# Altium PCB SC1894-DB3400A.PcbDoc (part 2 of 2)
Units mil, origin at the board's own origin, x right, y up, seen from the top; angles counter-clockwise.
Board outline 1800 x 1000 mil, 4 copper layers (L1 TOP, L2 GND, L3 PWR, L4  BOT), stack 35.4 mil thick; 130 components, 74 nets, 290 pads, 625 vias.

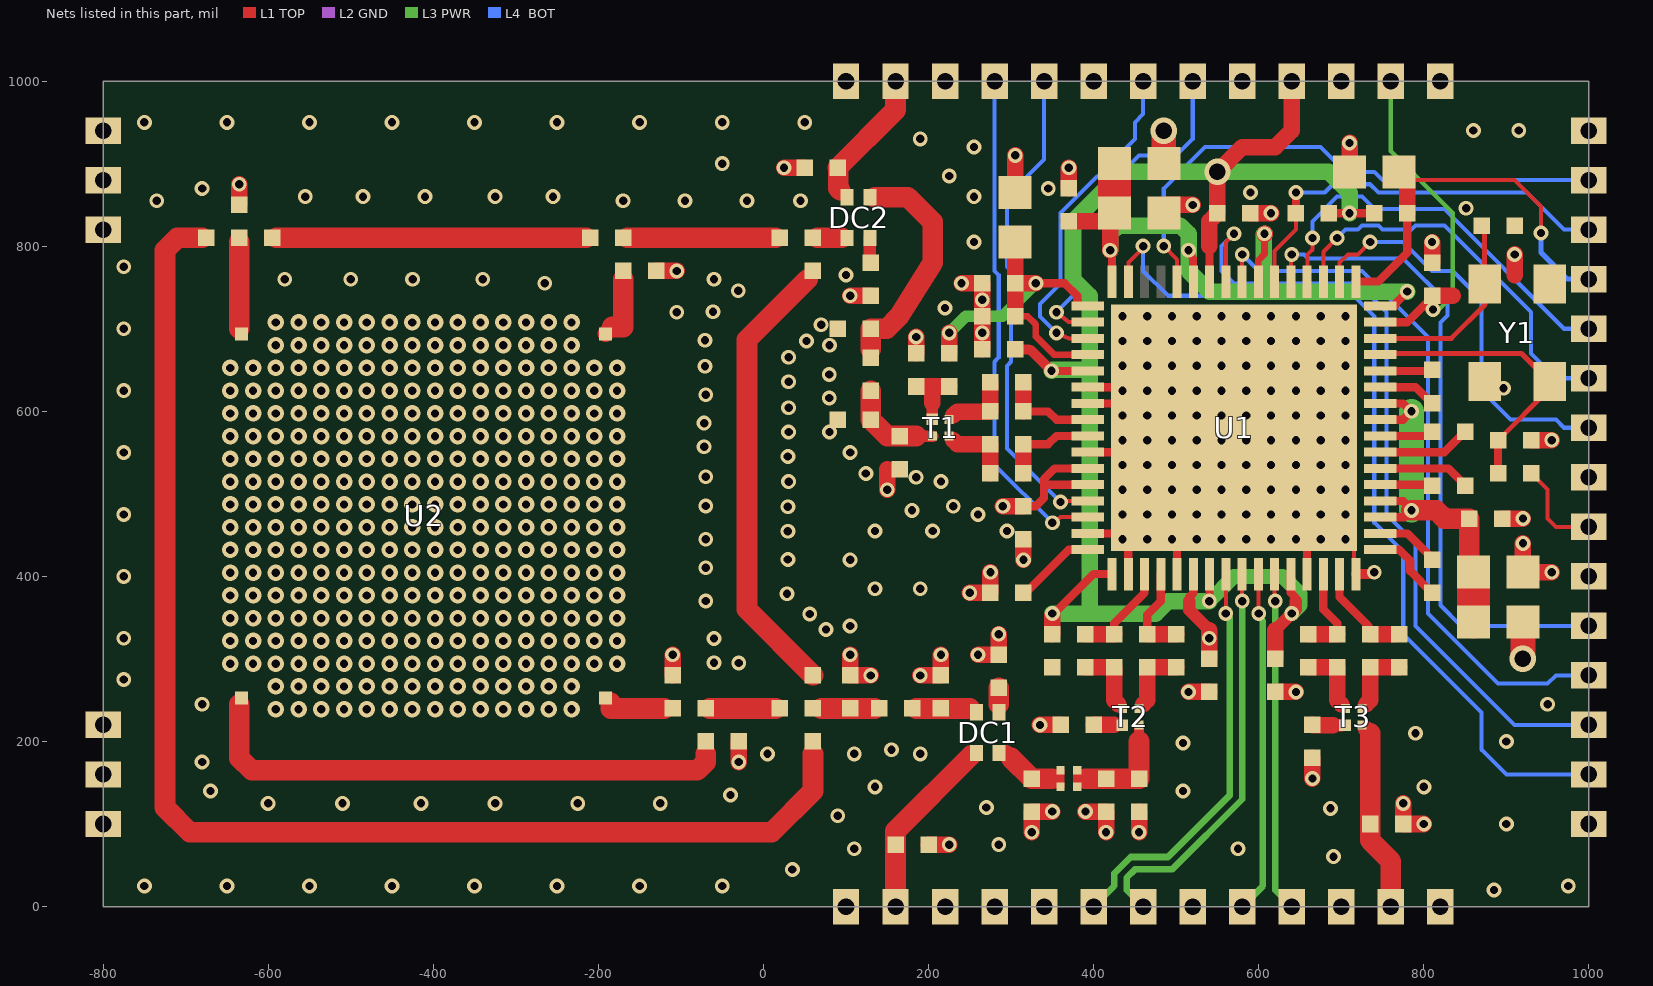
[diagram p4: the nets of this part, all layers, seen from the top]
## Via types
v1: diameter 20, hole 10, L1 TOP to L4  BOT, tented both sides, 308 vias
v2: diameter 18/18/18/18 (per signal layer), hole 10, L1 TOP to L4  BOT, tented both sides, 214 vias
v3: diameter 18/18/18/18 (per signal layer), hole 10, L1 TOP to L4  BOT, 100 vias
v4: diameter 32/32/32/32 (per signal layer), hole 20, L1 TOP to L4  BOT, tented both sides, 3 vias

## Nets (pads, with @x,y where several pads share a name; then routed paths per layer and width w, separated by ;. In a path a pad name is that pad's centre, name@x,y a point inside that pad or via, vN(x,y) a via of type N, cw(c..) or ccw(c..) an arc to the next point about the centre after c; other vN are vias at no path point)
+1.8V: C6.1 C8.1 C9.1 C12.1 C31.1 C34.1 FT1.2 FT2.1 FT3.1 P30.1 U1.1 U1.4 U1.11 U1.12 U1.22 U1.47 | length 1279.9
  L1 TOP w5: C8.1@810,740 C8.1@812.05,740
  L1 TOP w8: C12.1@305,715 320,715 330,705 330,690.58 352,668.58 U1.4@392.83,668.58
  L1 TOP w10: C31.1@315,485 330,485 340,495 340,511.1 ; v2(330,755) 365,755 380,740 380,727.64 U1.1@392.83,727.64 ; U1.12@392.83,511.1 340,511.1 ; U1.11@392.83,530.79 352.8,530.79 340,517.99 340,511.1 ; 515.79,370 515.79,375 520.79,380 U1.22@520.79,402.83 ; U1.47@747.17,707.95 780,707.95 C8.1@812.05,740
  L1 TOP w15: 515.79,370 515.79,359.21 540,335
  L1 TOP w20: FT3.1@225,670 v2(225,695) ; v2(290,485) C31.1@315,485 ; C12.1@305,715 C9.1@305,755 ; C6.1@305,805 C9.1@305,755 ; v2(330,755) C9.1@305,755 ; C34.1@540,300 v2(540,325) 540,335 ; C8.1@812.05,740 835,740
  L1 TOP w30: FT1.2@485,900 v4(485,940) ; v4(920,300) FT2.1@920,345
  L3 PWR w5: P30.1@760,1000 760,915 835,840 835,740 818.43,723.43 v2(811.02,723.43)
  L3 PWR w14: v2(225,695) 245,715 290,715 v2(330,755)
+3.3V: C3.2 C14.1 C33.1 C35.1 P32.1 R1.2 R2.1 U1.5 U1.17 U1.23 U1.28 U1.58 | length 2007.7
  L1 TOP w10: v2(349,649) 349.1,648.9 U1.5@392.83,648.9 ; v2@350,352.49 v2(350,355) 352.17,355 400,402.83 U1.17@422.36,402.83 ; v2(540,370) 540.47,370.47 U1.23@540.47,402.83 ; 540,800 540.47,799.53 U1.58@540.47,757.17 ; U1.28@638.9,402.83 638.9,380 645,373.9 645,370 ; R1.2@685,840 v2(710,840) R2.1@740,840
  L1 TOP w12: C14.1@305,675 321.34,675 322.17,674.17 323.83,674.17 v2(349,649)
  L1 TOP w15: 620,335 v2(640,355) 645,360 645,370
  L1 TOP w20: C33.1@350,330 v2@350,352.49 ; 540,800 540,830 C3.2@550,840 v4(550,890) 580,920 620,920 640,940 P32.1@640,1000 ; C35.1@620,300 620,335
  L3 PWR w18: v2(540,370) 570,400 628.75,400 650,378.75 650,365 v2(640,355)
  L3 PWR w20: v2(349,649) 350,650 395,650 ; v2(350,355) 395,355 ; v2(540,370) 490,370 475,355 395,355 ; v2(710,840) 710,865 685,890 v4(550,890) 435,890 375,830 375,760 395,740 395,650 ; 395,355 395,650
ADCIN0N: P7.1 U1.25 | length 495.6
  L1 TOP w5: U1.25@579.84,402.83 579.84,370 v2(580,370)
  L3 PWR w8: P7.1@460,0 440,20 440,35 450,45 495,45 580,130 v2(580,370)
ADCIN0P: P6.1 U1.24 | length 499.8
  L1 TOP w5: v2(560,355) 560.16,355 U1.24@560.16,402.83
  L3 PWR w8: P6.1@400,0 425,25 425,40 445,60 490,60 565,135 565,350 v2(560,355)
ADCIN1N: P10.1 U1.27 | length 411.9
  L1 TOP w5: U1.27@619.21,402.83 619.21,370 v2(620,370)
  L3 PWR w8: v2(620,370) 620,20 P10.1@640,0
ADCIN1P: P9.1 U1.26 | length 414.8
  L1 TOP w5: U1.26@599.53,402.83 599.53,355 v2(600,355)
  L3 PWR w8: P9.1@580,0 605,25 605,345 v2(600,355)
DGPIN0: P15.1 U1.63 | length 1104.3
  L1 TOP w5: U1.63@442.05,757.17 442.05,780 460,797.95 v2(460,800)
  L4  BOT w5: v2(460,800) 460,770 490,740 715,740 740,715 740,465 775,430 775,330 870,235 870,190 900,160 P15.1@1000,160
DGPIN1: P17.1 U1.56 | length 868.8
  L1 TOP w5: U1.56@579.84,757.17 579.84,790 v2(580,790)
  L4  BOT w5: v2(580,790) 600,770 725,770 805,690 805,355 890,270 950,270 960,280 P17.1@1000,280
EXTCLKIN: C15.2 P20.1 | length 117.4
  L1 TOP w5: C15.2@930,525 950,505 950,470 960,460 P20.1@1000,460
GND: C1.2 C2.1 C3.1 C4.2 C6.2 C8.2 C9.2 C10.2 C11.2 C12.2 C14.2 C22.2 C26.1 C28.1 C29.2 C30.2 C31.2 C33.2 C34.2 C35.2 C36.2 C45.2 C46.2 C47.2 C48.2 P1.1 P3.1 P4.1 P5.1 P8.1 P11.1 P13.1 P14.1 P19.1 P21.1 P28.1 P29.1 P31.1 P33.1 P36.1 P39.1 P41.1 P42.1 P43.1 P44.1 P45.1 P46.1 P47.1 R10.2 R12.1 R13.1 R15.2 R16.2 R21.1 R23.2 R43.1 R45.1 R98.1 R99.1 R104.1 R105.1 U1.6 U1.7 U1.10 U1.15 U1.18 U1.21 U1.29 U1.32 U1.65 Y1.2 Y1.4 | length 2638.1
  L1 TOP w5: v3(705,445) 715.47,445 715.47,405 U1.32@717.64,402.83
  L1 TOP w10: U1.15@392.83,452.05 U1.65@442.05,452.05 ; U1.10@392.83,550.47 U1.65@442.05,550.47 ; U1.7@392.83,609.53 U1.65@570,609.53 ; U1.6@392.83,629.21 570,629.21 U1.65@570,609.53 ; U1.18@442.05,402.83 U1.65@442.05,452.05 ; U1.21@501.1,402.83 U1.65@501.1,452.05 ; U1.29@658.58,402.83 658.58,580 U1.65@570,580 ; U1.65@442.05,452.05 U1.65@442.05,550.47 ; U1.65@442.05,452.05 U1.65@501.1,452.05 ; U1.65@442.05,550.47 U1.65@501.1,550.47 ; U1.65@501.1,452.05 U1.65@501.1,550.47 ; U1.65@501.1,550.47 501.1,580 U1.65@570,580 ; U1.65@501.1,550.47 570,550.47 U1.65@570,580 ; U1.65@570,580 U1.65@570,609.53
  L1 TOP w12: U1.32@717.64,402.83 737.83,402.83 v2(740,405)
  L1 TOP w20: R98.1@-635,850 v2(-635,875) ; R105.1@-130,770 v2(-105,770) ; R104.1@-110,280 v2(-110,305) ; v2(-30,175) R99.1@-30,200 ; v2(25,895) C48.2@50,895 ; v2(105,305) R13.1@105,280 v2(130,280) ; v2(105,740) R10.2@130,740 ; v2(150,505) 150,530 ; C26.1@185,670 v2(185,690) ; v2(190,280) R15.2@215,280 v2(215,305) ; C47.2@200,75 v2(225,75) ; v2(240,755) C9.2@265,755 v2(265,735) C12.2@265,715 v2(265,695) C14.2@265,675 ; v2(250,380) R12.1@275,380 v2(275,405) ; v2(260,305) R16.2@285,305 v2(285,330) ; C6.2@305,865 v2(305,910) ; v2(315,420) C31.2@315,445 ; v2(325,90) R21.1@325,115 v2(350,115) ; v2(335,220) C28.1@360,220 ; C4.2@370,870 v2(370,895) ; v2(390,115) R23.2@415,115 v2(415,90) ; v2(455,90) C46.2@455,115 ; C2.1@485,840 485,850 v2(520,850) ; v2(515,260) C34.2@540,260 ; C3.1@590,840 v2(615,840) ; C35.2@620,260 v2(645,260) ; v2(665,155) C36.2@665,180 ; C1.2@710,890 v2(710,925) ; v2(775,125) C45.2@775,100 v2(800,100) ; C8.2@810,780 v2(810,805) ; C29.2@895,470 v2(920,470) ; 910,765 v2(910,790) ; v2(920,440) C30.2@920,405 v2(955,405) ; C11.2@930,565 v2(955,565)
  L2 GND w20: P1.1@100,0 100,1.81 P1.1@100.69,2.5 ; P3.1@219.7,2.5 220,2.2 P3.1@220,0 ; P31.1@700,999.24 P31.1@701.74,997.5 ; P13.1@820,2.33 P13.1@820.17,2.5
  L3 PWR w20: P1.1@100,0 100,1.94 P1.1@100.56,2.5 ; P3.1@220,0 P3.1@220,2.5
  other v1: -590.79,239.09 -563.23,239.09 -535.67,239.09 -508.11,239.09 -480.55,239.09 -452.99,239.09 -425.43,239.09 -397.87,239.09 -370.32,239.09 -342.76,239.09 -315.2,239.09 -287.64,239.09 -260.08,239.09 -232.52,239.09 -590.79,266.65 -563.23,266.65 -535.67,266.65 -508.11,266.65 -480.55,266.65 -452.99,266.65 -425.43,266.65 -397.87,266.65 -370.32,266.65 -342.76,266.65 -315.2,266.65 -287.64,266.65 -260.08,266.65 -232.52,266.65 -645.91,294.21 -618.35,294.21 -590.79,294.21 -563.23,294.21 -535.67,294.21 -508.11,294.21 -480.55,294.21 -452.99,294.21 -425.43,294.21 -397.87,294.21 -370.32,294.21 -342.76,294.21 -315.2,294.21 -287.64,294.21 -260.08,294.21 -232.52,294.21 -204.96,294.21 -177.4,294.21 -645.91,321.77 -618.35,321.77 -590.79,321.77 -563.23,321.77 -535.67,321.77 -508.11,321.77 -480.55,321.77 -452.99,321.77 -425.43,321.77 -397.87,321.77 -370.32,321.77 -342.76,321.77 -315.2,321.77 -287.64,321.77 -260.08,321.77 -232.52,321.77 -204.96,321.77 -177.4,321.77 -645.91,349.33 -618.35,349.33 -590.79,349.33 -563.23,349.33 -535.67,349.33 -508.11,349.33 -480.55,349.33 -452.99,349.33 -425.43,349.33 -397.87,349.33 -370.32,349.33 -342.76,349.33 -315.2,349.33 -287.64,349.33 -260.08,349.33 -232.52,349.33 -204.96,349.33 -177.4,349.33 -645.91,376.89 -618.35,376.89 -590.79,376.89 -563.23,376.89 -535.67,376.89 -508.11,376.89 -480.55,376.89 -452.99,376.89 -425.43,376.89 -397.87,376.89 -370.32,376.89 -342.76,376.89 -315.2,376.89 -287.64,376.89 -260.08,376.89 -232.52,376.89 -204.96,376.89 -177.4,376.89 -645.91,404.45 -618.35,404.45 -590.79,404.45 -563.23,404.45 -535.67,404.45 -508.11,404.45 -480.55,404.45 -452.99,404.45 -425.43,404.45 -397.87,404.45 -370.32,404.45 -342.76,404.45 -315.2,404.45 -287.64,404.45 -260.08,404.45 -232.52,404.45 -204.96,404.45 -177.4,404.45 -645.91,432.01 -618.35,432.01 -590.79,432.01 -563.23,432.01 -535.67,432.01 -508.11,432.01 -480.55,432.01 -452.99,432.01 -425.43,432.01 -397.87,432.01 -370.32,432.01 -342.76,432.01 -315.2,432.01 -287.64,432.01 -260.08,432.01 -232.52,432.01 -204.96,432.01 -177.4,432.01 -645.91,459.57 -618.35,459.57 -590.79,459.57 -563.23,459.57 -535.67,459.57 -508.11,459.57 -480.55,459.57 -452.99,459.57 -425.43,459.57 -397.87,459.57 -370.32,459.57 -342.76,459.57 -315.2,459.57 -287.64,459.57 -260.08,459.57 -232.52,459.57 -204.96,459.57 -177.4,459.57 -645.91,487.13 -618.35,487.13 -590.79,487.13 -563.23,487.13 -535.67,487.13 -508.11,487.13 -480.55,487.13 -452.99,487.13 -425.43,487.13 -397.87,487.13 -370.32,487.13 -342.76,487.13 -315.2,487.13 -287.64,487.13 -260.08,487.13 -232.52,487.13 -204.96,487.13 -177.4,487.13 -645.91,514.68 -618.35,514.68 -590.79,514.68 -563.23,514.68 -535.67,514.68 -508.11,514.68 -480.55,514.68 -452.99,514.68 -425.43,514.68 -397.87,514.68 -370.32,514.68 -342.76,514.68 -315.2,514.68 -287.64,514.68 -260.08,514.68 -232.52,514.68 -204.96,514.68 -177.4,514.68 -645.91,542.24 -618.35,542.24 -590.79,542.24 -563.23,542.24 -535.67,542.24 -508.11,542.24 -480.55,542.24 -452.99,542.24 -425.43,542.24 -397.87,542.24 -370.32,542.24 -342.76,542.24 -315.2,542.24 -287.64,542.24 -260.08,542.24 -232.52,542.24 -204.96,542.24 -177.4,542.24 -645.91,569.8 -618.35,569.8 -590.79,569.8 -563.23,569.8 -535.67,569.8 -508.11,569.8 -480.55,569.8 -452.99,569.8 -425.43,569.8 -397.87,569.8 -370.32,569.8 -342.76,569.8 -315.2,569.8 -287.64,569.8 -260.08,569.8 -232.52,569.8 -204.96,569.8 -177.4,569.8 -645.91,597.36 -618.35,597.36 -590.79,597.36 -563.23,597.36 -535.67,597.36 -508.11,597.36 -480.55,597.36 -452.99,597.36 -425.43,597.36 -397.87,597.36 -370.32,597.36 -342.76,597.36 -315.2,597.36 -287.64,597.36 -260.08,597.36 -232.52,597.36 -204.96,597.36 -177.4,597.36 -645.91,624.92 -618.35,624.92 -590.79,624.92 -563.23,624.92 -535.67,624.92 -508.11,624.92 -480.55,624.92 -452.99,624.92 -425.43,624.92 -397.87,624.92 -370.32,624.92 -342.76,624.92 -315.2,624.92 -287.64,624.92 -260.08,624.92 -232.52,624.92 -204.96,624.92 -177.4,624.92 -645.91,652.48 -618.35,652.48 -590.79,652.48 -563.23,652.48 -535.67,652.48 -508.11,652.48 -480.55,652.48 -452.99,652.48 -425.43,652.48 -397.87,652.48 -370.32,652.48 -342.76,652.48 -315.2,652.48 -287.64,652.48 -260.08,652.48 -232.52,652.48 -204.96,652.48 -177.4,652.48 -590.79,680.04 -563.23,680.04 -535.67,680.04 -508.11,680.04 -480.55,680.04 -452.99,680.04 -425.43,680.04 -397.87,680.04 -370.32,680.04 -342.76,680.04 -315.2,680.04 -287.64,680.04 -260.08,680.04 -232.52,680.04 -590.79,707.6 -563.23,707.6 -535.67,707.6 -508.11,707.6 -480.55,707.6 -452.99,707.6 -425.43,707.6 -397.87,707.6 -370.32,707.6 -342.76,707.6 -315.2,707.6 -287.64,707.6 -260.08,707.6 -232.52,707.6
  other v2: 885,20 -750,25 -650,25 -550,25 -450,25 -350,25 -250,25 -150,25 -50,25 975,25 35,45 690.51,60.47 110,70 575,70 285,75 900,100 90,110 687.05,118.94 270,120 -600,125 -510,125 -415,125 -325,125 -225,125 -125,125 -40,135 -670,140 508.27,140 135,145 800,145 -680,175 5,185 110,185 190,185 155,190 508.27,198.03 900,200 790,210 -680,245 950,245 -775,275 -60.04,295.28 -30,295 -775,325 -60.04,324.8 75.79,335.63 105,340 56.1,354.33 -69.88,370.08 28.54,378.94 135,385 190,385 -775,400 -69.88,410.43 29.53,420.28 105,420 -69.88,444.88 29.53,454.72 135,455 205,455 295,455 -775,475 260,475 180,480 29.53,484.25 -69.88,485.24 230,485 30.51,514.76 215,515 185,520 -69.88,520.67 124.02,524.61 29.53,545.28 -775,550 105,550 -71.85,557.09 30.51,574.8 80,575 -71.85,585.63 30.51,604.33 79.72,616.14 -69.88,620.08 -775,625 896.65,627.95 30.51,635.83 79.72,644.68 -70.87,654.53 30.51,665.35 80,680 52.17,685.04 -70.87,686.02 -775,700 69.88,704.72 -105,720 -61.02,720.47 220,725 -30.51,746.06 -265,755 -580,760 -500,760 -425,760 -340,760 -60.04,759.84 100,765 -775,775 255,805 851.3,845.91 -735,855 -170,855 -95,855 -20,855 45,855 -555,860 -485,860 -410,860 -325,860 -255,860 255,860 590,865 -680,870 345,870 225,885 -50,900 255,920 190,930 860,940 915,940 -750,950 -650,950 -550,950 -450,950 -350,950 -250,950 -150,950 -50,950 50,950
  other v3: 435,445 465,445 495,445 525,445 555,445 585,445 615,445 645,445 675,445 435,475 465,475 495,475 525,475 555,475 585,475 615,475 645,475 675,475 705,475 435,505 465,505 495,505 525,505 555,505 585,505 615,505 645,505 675,505 705,505 435,535 465,535 495,535 525,535 555,535 585,535 615,535 645,535 675,535 705,535 435,565 465,565 495,565 525,565 555,565 585,565 615,565 645,565 675,565 705,565 435,595 465,595 495,595 525,595 555,595 585,595 615,595 645,595 675,595 705,595 435,625 465,625 495,625 525,625 555,625 585,625 615,625 645,625 675,625 705,625 435,655 465,655 495,655 525,655 555,655 585,655 615,655 645,655 675,655 705,655 435,685 465,685 495,685 525,685 555,685 585,685 615,685 645,685 675,685 705,685 435,715 465,715 495,715 525,715 555,715 585,715 615,715 645,715 675,715 705,715
LOADENB: P27.1 U1.60 | length 671.8
  L1 TOP w5: v2(485,800) 500.36,784.64 500.36,784.25 501.1,783.51 U1.60@501.1,757.17
  L4  BOT w5: v2(485,800) 485,870 535,920 675,920 705,890 740,890 750,880 P27.1@1000,880
MGPO0: P34.1 U1.2 | length 416.8
  L1 TOP w5: v2(355,720) 370,707.95 U1.2@392.83,707.95
  L4  BOT w5: v2(355,720) 380,745 380,835 455,910 500,910 520,930 P34.1@520,1000
MGPO1: P35.1 U1.3 | length 404.3
  L1 TOP w5: v2(355,695) 370,688.27 U1.3@392.83,688.27
  L4  BOT w5: v2(355,695) 335,715 335,730 360,755 360,840 450,930 450,950 460,960 P35.1@460,1000
MGPO2: P37.1 U1.13 | length 594
  L1 TOP w5: v2(360,490) 360,491.42 U1.13@392.83,491.42
  L4  BOT w5: P37.1@340,1000 340,905 295,860 295,775 300,770 300,660 295,655 295,555 v2(360,490)
MGPO3: P38.1 U1.14 | length 613
  L1 TOP w5: v2(350,465) 360,471.73 U1.14@392.83,471.73
  L4  BOT w5: P38.1@280,1000 280,770 285,765 285,665 280,660 280,535 v2(350,465)
N16778023: C11.1 C15.1 U1.45 Y1.3 | length 357.4
  L1 TOP w6: U1.45@747.17,668.58 747.17,670 918.27,670 Y1.3@952.32,635.94 952.32,627.32 C11.1@890,565
  L1 TOP w10: C15.1@890,525 C11.1@890,565
N16778042: C29.1 C30.1 FT2.2 U1.35 U1.36 U1.41 U1.42 | length 499.8
  L1 TOP w10: U1.35@747.17,471.73 776.73,471.73 v2(785,480) 785,481.42 775,491.42 U1.36@747.17,491.42 ; U1.41@747.17,589.84 775,589.84 775,590 v2(785,600) 784.53,600 775,609.53 U1.42@747.17,609.53
  L1 TOP w25: v2(785,480) 815,480 825,470 C29.1@855,470 855,400 C30.1@860,405
  L1 TOP w40: FT2.2@860,345 C30.1@860,405
  L3 PWR w30: v2(785,480) v2(785,600)
N16778055: C51.2 L2.2 U1.8 | length 117
  L1 TOP w10: C51.2@315,600 315.16,599.84 345,599.84 355,589.84 U1.8@392.83,589.84
  L1 TOP w20: C51.2@315,600 L2.2@315,635
N16778107: C52.2 L6.1 U1.20 | length 114.6
  L1 TOP w10: C52.2@465,330 465,353.58 481.42,370 U1.20@481.42,402.83
  L1 TOP w20: C52.2@465,330 L6.1@500,330
N16778109: C2.2 C4.1 FT1.1 U1.48 U1.55 U1.59 U1.64 | length 924.4
  L1 TOP w8: U1.55@599.53,757.17 599.53,783 607,790.47 v2@607,814.24
  L1 TOP w10: v2@420,802.36 420.98,795.13 421,795 422.36,785 U1.64@422.36,757.17 ; v2(515,795) 520.46,785.01 520.46,760.33 520.79,760 U1.59@520.79,757.17 ; U1.48@747.17,727.64 765,727.64 765,730 v2(780,745)
  L1 TOP w20: C4.1@370,830 C2.2@420,830 ; v2(420,795) 420,802.36 C2.2@420,830 ; C2.2@425,840 420,835 C2.2@420,830 ; FT1.1@425,895 FT1.1@425,900 ; v2@607,814.24 v2(607,815)
  L1 TOP w40: C2.2@425,840 FT1.1@425,895
  L3 PWR w20: v2(420,795) 420,815 430,825 505,825 515,815 v2(515,795) 515,769.99 539.99,744.99 ; v2(607,815) 606.29,814.29 606.29,744.99 ; v2(780,745) 775,745 606.29,744.99 ; 540,744.99 606.29,744.99 ; 539.99,744.99 606.29,744.99
N16778151: R11.2 R13.2 R14.2 R17.1 R101.1 | length 80
  L1 TOP w5: R101.1@60,240 70,240 ; R14.2@135,240 R14.2@140,240
  L1 TOP w25: 70,240 R13.2@105,240 R14.2@135,240
N16778208: C10.1 U1.46 Y1.1 | length 241.2
  L1 TOP w6: U1.46@747.17,688.27 833.27,688.27 874.02,729.02 874.02,753.62 Y1.1@873.58,754.06 873.58,821.26 C10.1@870,824.84
N16778603: C26.2 FT3.2 T1.1 | length 98.5
  L1 TOP w14: T1.1@204.5,590.5 204.5,610
  L1 TOP w20: 204.5,610 204.5,629.5 C26.2@185,630 FT3.2@225,630
N16778643: DC1.3 R21.2 R22.2 R24.2 | length 98.3
  L1 TOP w10: 350,155 360,155 ; R24.2@360,145 360,155 ; R22.2@360,165 360,155
  L1 TOP w20: 294.41,185.59 300,180
  L1 TOP w25: 300,180 R21.2@325,155 350,155
N16778760: R12.2 U1.16 | length 99.5
  L1 TOP w10: R12.2@315,380 317.64,380 370,432.36 U1.16@392.83,432.36
N16778848: L7.2 R25.1 U1.31 | length 123.2
  L1 TOP w10: U1.31@697.95,402.83 697.95,375 732.95,340 732.95,332.05 L7.2@735,330 ; R25.1@765,330 R25.1@770,330
  L1 TOP w20: L7.2@735,330 R25.1@765,330
N16778850: DC1.2 R14.1 R15.1 | length 70
  L1 TOP w5: R14.1@180,240 R14.1@185,240
  L1 TOP w25: R14.1@185,240 R15.1@215,240 DC1.2@250,240
N16778878: L7.1 R26.2 U1.30 | length 114.8
  L1 TOP w10: U1.30@678.27,402.83 678.27,360 695,343.27 L7.1@695,330
  L1 TOP w20: R26.2@660,330 L7.1@695,330
N16778942: C46.1 R22.1 R23.1 R24.1 T2.2 | length 200
  L1 TOP w10: R24.1@380,145 380,155 ; R22.1@380,165 380,155 ; 390,155 380,155
  L1 TOP w12: 455,200 T2.2@455,220
  L1 TOP w25: 390,155 C46.1@455,155 ; R23.1@415,155 C46.1@455,155 ; 455,200 C46.1@455,155
N16779024: C51.1 L3.1 U1.9 | length 117
  L1 TOP w10: C51.1@315,560 315.16,560.16 345,560.16 355,570.16 U1.9@392.83,570.16
  L1 TOP w20: L3.1@315,525 C51.1@315,560
N16779035: C52.1 L5.2 U1.19 | length 123
  L1 TOP w10: C52.1@425,330 425,343.27 461.73,380 U1.19@461.73,402.83
  L1 TOP w20: L5.2@390,330 C52.1@425,330
N16779391: C18.1 L5.1 T2.4 | length 89.1
  L1 TOP w5: T2.4@430,245 T2.4@435,240
  L1 TOP w20: L5.1@390,290 C18.1@425,290 425,250 T2.4@430,245
N16779395: C18.2 L6.2 T2.3 | length 89.1
  L1 TOP w5: T2.3@455,240 T2.3@460,245
  L1 TOP w20: T2.3@460,245 465,250 C18.2@465,290 L6.2@500,290
N16779627: C13.1 U1.44 | length 63.3
  L1 TOP w10: U1.44@747.17,648.9 808.9,648.9 C13.1@810,650
N16779631: C13.2 U1.43 | length 70.8
  L1 TOP w10: U1.43@747.17,629.21 790,629.21 809.21,610 C13.2@810,610
N16779697: C25.1 U1.40 | length 64.8
  L1 TOP w10: U1.40@747.17,570.16 805.16,570.16 C25.1@810,575
N16779756: C25.2 U1.39 | length 113
  L1 TOP w10: U1.39@747.17,550.47 825,550.47 849.53,575 C25.2@850,575
N16779783: C27.1 U1.38 | length 111.9
  L1 TOP w10: U1.38@747.17,530.79 830,530.79 850,510.79 C27.1@850,510
N16779788: DC2.3 R10.1 | length 31.8
  L1 TOP w15: DC2.3@128.78,810.59 128.78,780 R10.1@130,780
N16779793: C27.2 U1.37 | length 63.9
  L1 TOP w10: U1.37@747.17,511.1 810,511.1 C27.2@810,510
N16779834: C32.1 U1.34 | length 77.3
  L1 TOP w10: U1.34@747.17,452.05 780,452.05 810,422.05 C32.1@810,420
N16779938: C32.2 U1.33 | length 91.8
  L1 TOP w10: U1.33@747.17,432.36 770,432.36 783.68,418.68 783.68,406.32 C32.2@810,380
N16779945: DC1.4 R16.1 | length 21.7
  L1 TOP w5: DC1.4@283.78,243.78 DC1.4@285,245
  L1 TOP w25: DC1.4@285,245 R16.1@285,265
N16780104: C20.1 R26.1 T3.4 | length 89.1
  L1 TOP w5: T3.4@700,245 T3.4@705,240
  L1 TOP w20: R26.1@660,290 C20.1@695,290 695,250 T3.4@700,245
N16780111: C20.2 R25.2 T3.3 | length 89.1
  L1 TOP w5: T3.3@725,240 T3.3@730,245
  L1 TOP w20: T3.3@730,245 735,250 C20.2@735,290 R25.2@770,290
N16780222: C17.1 L2.1 T1.4 | length 89.1
  L1 TOP w5: T1.4@225,590 T1.4@230,595
  L1 TOP w20: T1.4@230,595 234.68,599.68 274.68,599.68 C17.1@275,600 L2.1@275,635
N16780244: C17.2 L3.2 T1.3 | length 89.1
  L1 TOP w5: T1.3@225,570 T1.3@230,565
  L1 TOP w20: T1.3@230,565 234.68,560.32 274.68,560.32 C17.2@275,560 L3.2@275,525
N16798679: R102.2 R105.2 U2.2 | length 92.6
  L1 TOP w5: R102.2@-170,760 R102.2@-170,770
  L1 TOP w20: U2.2@-191.18,693.82 -183,702
  L1 TOP w25: -183,702 -170,702 R102.2@-170,760
N16798683: R97.1 R104.2 U2.1 | length 81.7
  L1 TOP w5: R104.2@-120,240 R104.2@-110,240
  L1 TOP w25: U2.1@-185,246.69 -185,240 R104.2@-120,240
N16798687: R96.1 R99.2 U2.4 | length 665.4
  L1 TOP w5: -70,185 R96.1@-70,200
  L1 TOP w25: U2.4@-635,245 -635,180 -620,165 -80,165 -70,175 -70,185
N16798691: R95.2 R98.2 R100.2 U2.3 | length 110
  L1 TOP w5: R100.2@-635,805 R100.2@-635,810
  L1 TOP w25: U2.3@-635,700 R100.2@-635,805
N16798746: R8.2 R102.1 R103.1 | length 190
  L1 TOP w5: R102.1@-170,810 R102.1@-165,810 ; R8.2@15,810 R8.2@20,810
  L1 TOP w25: R102.1@-165,810 R8.2@15,810
N16798748: DC2.1 R8.1 R9.2 | length 35.7
  L1 TOP w5: R8.1@60,810 R8.1@65,810 ; DC2.1@95,810 DC2.1@95.51,810.51
  L1 TOP w25: R8.1@65,810 DC2.1@95,810
N16798750: R100.1 R103.2 | length 385
  L1 TOP w5: R100.1@-595,810 R100.1@-590,810 ; R103.2@-215,810 R103.2@-210,810
  L1 TOP w25: R100.1@-590,810 R103.2@-215,810
N16798758: R17.2 R96.2 R97.2 | length 95.7
  L1 TOP w5: R96.2@-72.68,235 R96.2@-70,240 R96.2@-65,240 ; R17.2@15,240 R17.2@20,240
  L1 TOP w25: R96.2@-65,240 R17.2@15,240
N16798802: R95.1 R101.2 | length 1609.4
  L1 TOP w5: R95.1@-680,810 R95.1@-675,810 ; 60,185 R101.2@60,200
  L1 TOP w25: R95.1@-680,810 -710,810 -725,795 -725,120 -695,90 10,90 60,140 60,185
N16798884: 
N16798892: 
N16798938: 
N16821465: C28.2 T2.1 | length 34.7
  L1 TOP w5: 425,220 425.5,219.5 T2.1@434.5,219.5
  L1 TOP w20: C28.2@400,220 425,220
N16831110: C36.1 T3.1 | length 39.7
  L1 TOP w5: T3.1@700,219.5 T3.1@704.5,219.5
  L1 TOP w15: 690,219.5 T3.1@700,219.5
  L1 TOP w20: C36.1@665,220 665.5,219.5 690,219.5
N16839032: C22.1 R44.1 R45.2 T1.2 | length 111.2
  L1 TOP w14: 185,570 T1.2@205,570
  L1 TOP w25: R45.2@130,590 R44.1@130,625 ; R45.2@135,585 150,570 C22.1@165,570 185,570
RESETN: C1.1 P25.1 R2.2 U1.49 | length 492.3
  L1 TOP w5: C1.1@775.6,880 780,880 910,880 941.93,848.07 v2(941.93,815.94)
  L1 TOP w10: U1.49@717.64,757.17 745,757.17 780,792.17 R2.2@780,833.6 ; C1.1@770,890 C1.1@775.6,880
  L1 TOP w20: C1.1@775.6,880 776.8,887.2 780,884 780,880 R2.2@780,840
  L4  BOT w6: v2(941.93,815.94) 941.93,792.32 974.25,760 P25.1@1000,760
RFFB: C45.1 P12.1 T3.2 | length 234.6
  L1 TOP w5: T3.2@725,220 T3.2@730,215
  L1 TOP w20: T3.2@730,215 735,210 ; 735,80.14 737,78.14
  L1 TOP w25: 735,80.14 C45.1@735,100 735,210 ; 737,78.14 760.14,55 760.14,29.97 P12.1@760,0
RFIN: C47.1 DC1.1 P2.1 | length 221.3
  L1 TOP w25: P2.1@160,0 C47.1@160,75 160,91.5 DC1.1@251.82,183.31
RFOUT: C48.1 DC2.2 P40.1 | length 162.3
  L1 TOP w25: 92.82,867.82 90.63,870 90.63,894.37 C48.1@90,895 160,965 P40.1@160,1000
RFOUTCPL_CPL: DC2.4 R43.2 R44.2 | length 274
  L1 TOP w25: 130,675 R43.2@130,700 149.27,700 164.55,715.28 205,780 205,829.41 175,859.41 DC2.4@135,859.41
SCLK: P23.1 U1.51 | length 481
  L1 TOP w5: U1.51@678.27,757.17 678.27,793.27 v2(695,810)
  L4  BOT w5: v2(695,810) 705,820 720,820 725,825 745,825 750,820 785,820 790,825 825,825 930,720 930,670 960,640 P23.1@1000,640
SDI: P18.1 U1.53 | length 807.1
  L1 TOP w5: U1.53@638.9,757.17 638.9,790 v2(640,790)
  L4  BOT w5: v2(640,790) 655,790 660,785 775,785 828.52,731.48 828.52,716.18 820,707.65 820,365 845,340 P18.1@1000,340
SDO: P26.1 R1.1 U1.54 | length 500.4
  L1 TOP w5: U1.54@619.21,757.17 619.21,794.21 645,820 R1.1@645,840
  L1 TOP w10: R1.1@645,840 v2(645,865)
  L4  BOT w5: v2(645,865) 680,865 690,875 735,875 745,865 925,865 970,820 P26.1@1000,820
SSN: P24.1 U1.52 | length 489.2
  L1 TOP w5: U1.52@658.58,757.17 658.58,760 659.29,760.71 659.29,790 665,795.71 v2(665,810)
  L4  BOT w5: v2(665,810) 665,830 695,860 725,860 740,845 825,845 970,700 P24.1@1000,700
STATO: P16.1 U1.57 | length 988
  L1 TOP w5: U1.57@560.16,757.17 560.16,805 570,814.84 v2(570,815)
  L4  BOT w5: v2(570,815) 555,800 555,770 570,755 720,755 755,720 755,475 790,440 790,340 910,220 P16.1@1000,220
ThruPath2: R9.1 R11.1 | length 543.6
  L1 TOP w25: R9.1@53.5,760 -20,686.5 -20,360 R11.1@60,280
WDTENB: P22.1 U1.50 | length 492.9
  L1 TOP w5: U1.50@697.95,757.17 697.95,780 707.95,790 720,790 v2(735,805)
  L4  BOT w5: v2(735,805) 775,805 810,770 835,770 870,735 870,625 905,590 960,590 970,580 P22.1@1000,580
pads on no net: U1.61 U1.62

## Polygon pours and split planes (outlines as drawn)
+1.8V on L3 PWR "L3 PWR-+1.8V" (solid, remove dead copper, pour order 2): 260,990 990,990 990,270 260,270
GND on L3 PWR "L3 PWR-GND" (solid, remove dead copper, pour order 4): -790,990 250,990 250,260 990,260 990,10 -790,10
GND on L2 GND "L2 GND-GND" (solid, remove dead copper, pour order 10): -790,990 990,990 990,10 -790,10
GND on L4  BOT "L4  BOT-GND" (solid, remove dead copper, pour order 8): -790,990 990,990 990,10 -790,10
GND on L1 TOP "L1 TOP-GND" (solid, pour order 6): -790,990 990,990 990,10 -790,10

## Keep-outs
Keep-Out Layer:
  the board outline again, w1

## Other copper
L1 TOP:
  region net GND: 531,0 509,0 509,35 531,35 531,0
  region net GND: -765,171 -765,149 -800,149 -800,171 -765,171
  region net GND: -765,231 -765,209 -800,209 -800,231 -765,231
  region net GND: 1000,111 1000,89 965,89 965,111 1000,111
  region net GND: 1000,531 1000,509 965,509 965,531 1000,531
  region net GND: 291,0 269,0 269,35 291,35 291,0
  region net GND: 351,0 329,0 329,35 351,35 351,0
  region net GND: -765,891 -765,869 -800,869 -800,891 -765,891
  region net GND: -765,111 -765,89 -800,89 -800,111 -765,111
  region net GND: 111,0 89,0 89,35 111,35 111,0
  region net GND: 111,965 89,965 89,1000 111,1000 111,965
  region net GND: 711,0 689,0 689,35 711,35 711,0
  region net GND: 231,0 209,0 209,35 231,35 231,0
  region net GND: 591,965 569,965 569,1000 591,1000 591,965
  region net GND: -765,831 -765,809 -800,809 -800,831 -765,831
  region net GND: 1000,411 1000,389 965,389 965,411 1000,411
  region net GND: -765,951 -765,929 -800,929 -800,951 -765,951
  region net GND: 411,965 389,965 389,1000 411,1000 411,965
  region net GND: 1000,951 1000,929 965,929 965,951 1000,951
  region net GND: 831,0 809,0 809,35 831,35 831,0
  region net GND: 711,965 689,965 689,1000 711,1000 711,965
  region net GND: 231,965 209,965 209,1000 231,1000 231,965
  region net GND: 831,965 809,965 809,1000 831,1000 831,965
  region net GND: -668.62,672.64 -668.62,275 -599.96,275 -599.96,215 -213.9,215 -213.9,272.57 -186.34,272.57 -186.34,281.89 -156.81,281.89 -156.81,665.75 -186.34,665.75 -186.34,672.64 -213.9,672.64 -213.9,762.2 -601.69,762.2 -601.69,672.64
  text "L1 TOP" at 34.25,-756.5 h50
L2 GND:
  rectangle net GND: -670,210 -145,735
  region net GND: 411,965 389,965 389,1000 411,1000 411,965
  region net GND: 351,0 329,0 329,35 351,35 351,0
  region net GND: -800,809 -800,831 -765,831 -765,809 -800,809
  region net GND: 231,0 209,0 209,35 231,35 231,0
  region net GND: -800,869 -800,891 -765,891 -765,869 -800,869
  region net GND: 1000,531 1000,509 965,509 965,531 1000,531
  region net GND: -800,89 -800,111 -765,111 -765,89 -800,89
  region net GND: 111,0 89,0 89,35 111,35 111,0
  region net GND: 111,965 89,965 89,1000 111,1000 111,965
  region net GND: 291,0 269,0 269,35 291,35 291,0
  region net GND: 965,89 965,111 1000,111 1000,89 965,89
  region net GND: 831,965 809,965 809,1000 831,1000 831,965
  region net GND: 531,0 509,0 509,35 531,35 531,0
  region net GND: 591,965 569,965 569,1000 591,1000 591,965
  region net GND: -800,149 -800,171 -765,171 -765,149 -800,149
  region net GND: 831,0 809,0 809,35 831,35 831,0
  region net GND: 711,0 689,0 689,35 711,35 711,0
  region net GND: -800,929 -800,951 -765,951 -765,929 -800,929
  region net GND: 231,965 209,965 209,1000 231,1000 231,965
  region net GND: 711,965 689,965 689,1000 711,1000 711,965
  region net GND: -800,209 -800,231 -765,231 -765,209 -800,209
  region net GND: 965,389 965,411 1000,411 1000,389 965,389
  region net GND: 965,929 965,951 1000,951 1000,929 965,929
  text "L2 GND" at 34.25,-756.5 h50
L3 PWR:
  rectangle net GND: -680,215 -150,750
  region net GND: 509,35 531,35 531,0 509,0 509,35
  region net GND: 689,35 711,35 711,0 689,0 689,35
  region net GND: 809,35 831,35 831,0 809,0 809,35
  region net GND: -800,809 -800,831 -765,831 -765,809 -800,809
  region net GND: 269,35 291,35 291,0 269,0 269,35
  region net GND: 965,89 965,111 1000,111 1000,89 965,89
  region net GND: 209,35 231,35 231,0 209,0 209,35
  region net GND: -800,869 -800,891 -765,891 -765,869 -800,869
  region net GND: -800,149 -800,171 -765,171 -765,149 -800,149
  region net GND: 389,1000 411,1000 411,965 389,965 389,1000
  region net GND: 329,35 351,35 351,0 329,0 329,35
  region net GND: 89,35 111,35 111,0 89,0 89,35
  region net GND: -800,929 -800,951 -765,951 -765,929 -800,929
  region net GND: -800,209 -800,231 -765,231 -765,209 -800,209
  region net +1.8V: 744,1000 776,1000 776,945 744,945 744,1000
  region net GND: 89,1000 111,1000 111,965 89,965 89,1000
  region net GND: 209,1000 231,1000 231,965 209,965 209,1000
  region net GND: -800,89 -800,111 -765,111 -765,89 -800,89
  text "L3 PWR" at 34.25,-756.5 h50
L4  BOT:
  rectangle net GND: -665,215 -150,725
  region net GND: 965,384 965,416 1000,416 1000,384 965,384
  region net GND: 804,1000 836,1000 836,965 804,965 804,1000
  region net GND: -800,924 -800,956 -765,956 -765,924 -800,924
  region net GND: -800,84 -800,116 -765,116 -765,84 -800,84
  region net GND: 324,35 356,35 356,0 324,0 324,35
  region net GND: 384,1000 416,1000 416,965 384,965 384,1000
  region net GND: 504,35 536,35 536,0 504,0 504,35
  region net GND: 684,1000 716,1000 716,965 684,965 684,1000
  region net GND: 204,1000 236,1000 236,965 204,965 204,1000
  region net GND: 684,35 716,35 716,0 684,0 684,35
  region net GND: 84,1000 116,1000 116,965 84,965 84,1000
  region net GND: 204,35 236,35 236,0 204,0 204,35
  region net GND: -800,864 -800,896 -765,896 -765,864 -800,864
  region net GND: -800,804 -800,836 -765,836 -765,804 -800,804
  region net GND: -800,204 -800,236 -765,236 -765,204 -800,204
  region net GND: 965,504 965,536 1000,536 1000,504 965,504
  region net GND: 84,35 116,35 116,0 84,0 84,35
  region net GND: 264,35 296,35 296,0 264,0 264,35
  region net GND: 564,1000 596,1000 596,965 564,965 564,1000
  region net GND: -800,144 -800,176 -765,176 -765,144 -800,144
  region net GND: 965,84 965,116 1000,116 1000,84 965,84
  region net GND: 965,924 965,956 1000,956 1000,924 965,924
  region net GND: 804,35 836,35 836,0 804,0 804,35
  text "RDB3.4 REV3" at -725,365 h25 r270
  text "L4 BOT" at 34.25,-756.5 h50
Multi-Layer:
  text "SCINTERA" at 50,-300 h50
  text "SC1894-DB3400A  ASSEMBLY DRAWING" at 50,-450 h50
  text "(RDB3.4 REV3)" at 50,-590.75 h50

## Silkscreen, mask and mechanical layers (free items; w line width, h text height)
Silkscreen Top:
  circle w10: c91.54,780.51 r2.2
  circle w10: c255.91,155.51 r2.2
  region: 80,60 120,60 100,30 80,60
  region: 840,265 960,265 960,40 840,40 840,265
  text "SCINTERA" at -654.29,905 h35
  text "RDB3.4 REV3" at -385,905 h35
  text "SILK TOP" at 34.25,-756.5 h50
Paste Mask Top:
  text "PASTE TOP" at 34.25,-756.5 h50
Solder Mask Top:
  rectangle: -44.29,367.13 7.87,683.07
  region: 715,75 765,75 780,60 780,15 740,15 740,50 715,75
  region: -95,195 -95,140 -660,140 -660,195 -95,195
  region: -120,840 -120,785 5,785 5,840 -120,840
  region: 225,180 255,150 185,80 185,25 135,25 135,105 215,185 225,185 225,180
  region: 710,195 755,195 755,130 710,130 710,195
  region: 40,180 85,180 85,130 15,60 -705,60 -750,105 -750,805 -720,835 -695,835 -695,135 -680,120 5,120 40,155 40,180
  region: -565,840 -240,840 -240,780 -565,780 -565,840
  region: 130,965 85,920 145,920 190,965 130,965
  region: 164.37,838.58 194.88,869.09 194.88,871.06 196.85,871.06 229.33,838.58 229.33,767.72 217.52,755.91 164.37,755.91
  text "SOLDERMASK TOP" at 34.25,-756.5 h50
Solder Mask Bottom:
  region: 650,725 715,725 715,660 650,660 650,725
  region: 575,500 640,500 640,435 575,435 575,500
  region: 500,650 565,650 565,585 500,585 500,650
  region: 500,575 565,575 565,510 500,510 500,575
  region: 500,725 565,725 565,660 500,660 500,725
  region: 425,725 490,725 490,660 425,660 425,725
  region: 425,650 490,650 490,585 425,585 425,650
  region: 425,500 490,500 490,435 425,435 425,500
  region: 575,725 640,725 640,660 575,660 575,725
  region: 575,575 640,575 640,510 575,510 575,575
  region: 650,500 715,500 715,435 650,435 650,500
  region: 575,650 640,650 640,585 575,585 575,650
  region: 425,575 490,575 490,510 425,510 425,575
  region: 650,650 715,650 715,585 650,585 650,650
  region: 500,500 565,500 565,435 500,435 500,500
  region: 650,575 715,575 715,510 650,510 650,575
  text "SOLDERMASK BOT" at 34.25,-756.5 h50
Assembly Drawing Top:
  lines w5: -558.12,1369.08 -77.42,1369.08 ; -552.74,1378.04 -93.99,1378.04 ; -547.37,1387 -305,1387 ; -541.99,1395.96 -314.41,1395.96 ; -537.06,1404.92 -378.47,1404.92 ; -532.14,1413.88 -387.43,1413.88 ; -527.21,1422.84 -396.39,1422.84 ; -521.83,1431.8 -405.8,1431.8 ; -516.46,1440.76 -406.7,1440.76 ; -511.08,1449.72 -407.59,1449.72 ; -506.6,1458.68 -408.94,1458.68 ; -500.78,1467.64 -409.83,1467.64 ; -495.85,1476.6 -410.73,1476.6 ; -491.37,1485.56 -411.62,1485.56 ; -485.99,1494.52 -412.97,1494.52 ; -481.06,1503.48 -414.31,1503.48 ; -475.24,1512.44 -415.66,1512.44 ; -470.31,1521.4 -416.55,1521.4 ; -465.38,1530.36 -411.62,1530.36 ; -460.01,1539.32 -407.59,1539.32 ; -454.63,1548.28 -415.66,1548.28 ; -449.26,1557.24 -431.78,1557.24 ; -434.92,1584.12 -379.37,1584.12 ; -429.54,1593.08 -372.2,1593.08 ; -424.62,1602.04 -366.38,1602.04 ; -423.27,1575.16 -385.64,1575.16 ; -419.24,1611 -360.1,1611 ; -414.31,1619.96 -351.14,1619.96 ; -408.94,1628.92 -341.29,1628.92 ; -406.25,1566.2 -391.46,1566.2 ; -404.9,1543.35 -416.1,1520.95 -404.9,1431.35 -371.3,1397.75 -360.1,1397.75 ccw(c-365.95,1414.55) -360.1,1431.35 -371.3,1509.75 -360.55,1519.16 ; -403.56,1637.88 -312.17,1637.88 ; -399.08,1646.84 -263.34,1646.84 ; -395.05,1560.82 -360.1,1610.55 -337.7,1632.95 -214.5,1655.35 ; -393.7,1655.8 -214.5,1655.8 ; -388.78,1664.76 -219.43,1664.76 ; -383.4,1673.72 -224.36,1673.72 ; -378.92,1682.68 -229.74,1682.68 ; -373.54,1691.64 -235.11,1691.64 ; -368.17,1700.6 -239.59,1700.6 ; -362.79,1709.56 -245.42,1709.56 ; -361.45,1440.76 -356.97,1440.76 ; -360.1,1431.8 -339.5,1431.8 ; -360.1,1442.55 -315.3,1420.15 ; -357.86,1718.52 -249.9,1718.52 ; -352.94,1727.48 -255.72,1727.48 ; -351.14,1404.92 -317.99,1404.92 ; -350.25,1422.84 -320.23,1422.84 ; -348.46,1413.88 -318.44,1413.88 ; -347.56,1736.44 -260.65,1736.44 ; -345.32,1533.94 -315.3,1543.35 -270.5,1498.55 ; -342.63,1745.4 -265.13,1745.4 ; -337.26,1754.36 -271.4,1754.36 ; -332.33,1763.32 -276.33,1763.32 ; -330.09,1502.14 -330.09,1468.54 -296.49,1446.14 ; -326.95,1772.28 -281.26,1772.28 ; -322.02,1781.24 -287.08,1781.24 ; -316.65,1790.2 -291.56,1790.2 ; -311.27,1799.16 -296.04,1799.16 ; -306.34,1808.12 -301.42,1808.12 ; -304.55,1387 -111.02,1387 ; -294.7,1395.96 -127.14,1395.96 ; -285.74,1404.92 -145.06,1404.92 ; -281.7,1408.95 -259.3,1408.95 ccw(c-269.99,1412.82) -265.58,1423.29 ; -281.26,1476.6 -281.7,1476.6 -304.1,1431.35 ccw(c-292.89,1408.95) -304.11,1386.55 -236.9,1453.75 ; -270.95,1494.97 -270.95,1498.55 ; -263.34,1422.84 -179.56,1422.84 ; -259.3,1431.35 -236.9,1431.35 ccw(c-249.11,1431.94) -244.97,1443.45 ; -257.96,1413.88 -161.19,1413.88 ; -240.94,1440.76 -213.16,1440.76 ; -240.94,1449.72 -229.29,1449.72 ; -236.46,1431.8 -195.24,1431.8 ; -222.12,1468.09 -214.5,1476.15 -192.1,1543.35 -165.22,1569.34 ; -219.43,1467.64 -106.09,1467.64 ; -214.5,1476.6 -111.91,1476.6 ; -211.37,1485.56 -116.39,1485.56 ; -208.23,1494.52 -121.77,1494.52 ; -205.1,1503.48 -127.14,1503.48 ; -202.86,1458.68 -101.16,1458.68 ; -201.96,1512.44 -132.07,1512.44 ; -199.27,1521.4 -137,1521.4 ; -195.69,1530.36 -142.82,1530.36 ; -193,1539.32 -148.2,1539.32 ; -186.28,1449.72 -96.23,1449.72 ; -186.28,1548.28 -153.13,1548.28 ; -177.32,1557.24 -157.61,1557.24 ; -168.81,1440.76 -90.41,1440.76 ; -168.36,1566.2 -162.98,1566.2 ; -152.68,1431.8 -85.03,1431.8 ; -136.1,1422.84 -81,1422.84 ; -119.53,1413.88 -76.07,1413.88 ; -102.06,1404.92 -70.7,1404.92 ; -85.48,1395.96 -65.32,1395.96 ; -68.01,1387 -59.5,1387 ; -561.26,1363.7 -66.22,1363.7 -445.67,1564.41 -561.26,1363.7 ; -436.26,1581.88 -304.1,1812.6 -55.91,1380.28 -436.26,1581.88
  text "ALL PROCESSES MUST BE ROHS COMPLIANT." at -665,1990 h60
  text "CAUTION" at 520,1787 h60
  text "THIS ASSEMBLY INCORPORATES" at 345,1712 h30
  text "STATIC SENSITIVE DEVICES" at 420,1637 h30
  text "ASSEMBLY AND HANDLING MUST BE DONE AT AN" at 145,1562 h30
  text "APPROVED STATIC FREE STATION" at 370,1487 h30
  text "CAUTION" at 545,1362 h60
  text "GND" at 110,1070 h20 r90
  text "RFOUT" at 170,1070 h20 r90
  text "GND" at 230,1070 h20 r90
  text "MGPO3" at 300,1070 h20 r90
  text "MGPO2" at 360,1070 h20 r90
  text "GND" at 420,1070 h20 r90
  text "MGPO1" at 480,1070 h20 r90
  text "MGPO0" at 540,1070 h20 r90
  text "GND" at 595,1070 h20 r90
  text "+3.3V" at 650,1070 h20 r90
  text "GND" at 710,1070 h20 r90
  text "+1.8V" at 770,1070 h20 r90
  text "GND" at 830,1070 h20 r90
  text "GND" at -945,930 h20
  text "GND" at 1115,930 h20
  text "GND" at -945,870 h20
  text "LOADENB" at 1115,870 h20
  text "GND" at -945,810 h20
  text "SDO" at 1115,810 h20
  text "RESETN" at 1115,745 h20
  text "SSN" at 1115,690 h20
  text "SCLK" at 1115,630 h20
  text "WDTENB" at 1115,570 h20
  text "GND" at 1115,510 h20
  text "EXTCLKIN" at 1115,445 h20
  text "GND" at 1115,385 h20
  text "SDI" at 1115,325 h20
  text "DGPIN1" at 1115,270 h20
  text "STATO" at 1120,210 h20
  text "GND" at -940,205 h20
  text "DGPIN0" at 1115,155 h20
  text "GND" at -940,145 h20
  text "GND" at 1120,90 h20
  text "GND" at -940,85 h20
  text "GND" at 110,-170 h20 r90
  text "RFIN" at 170,-170 h20 r90
  text "GND" at 230,-170 h20 r90
  text "GND" at 295,-170 h20 r90
  text "GND" at 355,-170 h20 r90
  text "ADCIN0P" at 415,-170 h20 r90
  text "ADCIN0N" at 475,-170 h20 r90
  text "GND" at 530,-170 h20 r90
  text "ADCIN1P" at 590,-170 h20 r90
  text "ADCIN1N" at 650,-170 h20 r90
  text "GND" at 710,-170 h20 r90
  text "RFFB" at 770,-170 h20 r90
  text "GND" at 830,-170 h20 r90
  text "ASSY TOP" at 684.25,-756.5 h50
Drill Drawing:
  lines w1: -700,1050 -699.97,1050 ; -700,1100 -700,1240 ; -26.59,1190 -700,1190 ; 326.59,1190 1000,1190 ; 985,1000 985.03,1000 ; 1000,0 1000.03,0 ; 1000,1045 1000.03,1045 ; 1000,1095 1000,1240 ; 1035,1000 1290,1000 ; 1050,0 1290,0 ; 1240,432.5 1240,0 ; 1240,567.5 1240,1000 ; 2690,-1310 2690.03,-1310 ; 2700,-380 2700.03,-380 ; -700,1190 -600,1215 -600,1165 -700,1190 ; 1000,1190 900,1165 900,1215 1000,1190 ; 1240,0 1215,100 1265,100 1240,0 ; 1240,1000 1265,900 1215,900 1240,1000 ; 2740,-1310 4690,-1310 4690,-1260 2740,-1260 2740,-1310 ; 2740,-1010 4690,-1010 4690,-960 2740,-960 2740,-1010 ; 2740,-710 4690,-710 4690,-660 2740,-660 2740,-710 ; 2740,-410 4690,-410 4690,-360 2740,-360 2740,-410 ; 2840,-1260 4590,-1260 4590,-1010 2840,-1010 2840,-1260 ; 2840,-960 4590,-960 4590,-710 2840,-710 2840,-960 ; 2840,-660 4590,-660 4590,-410 2840,-410 2840,-660
  lines w10: 2259,-1310 2640,-1310 ; 2259,-380 2650,-380 ; 2309,-1460 2309,-1310 ; 2309,-230 2309,-380 ; 2309,-1310 2334,-1410 2284,-1410 2309,-1310 ; 2309,-380 2284,-280 2334,-280 2309,-380
  text "NOTES: (UNLESS OTHERWISE SPECIFIED)" at 2210,3075 h60
  text "1) FINISHED BOARD THICKNESS TO BE 42 MILS +/- 10%." at 2190,2790 h50
  text "2) SOLDERMASK TO BE LPI, COLOR : GREEN, BOTH SIDES." at 2190,2640 h50
  text "3) PLATING:  IMMERSION GOLD OVER ELECTROLESS NICKEL." at 2190,2490 h50
  text "- ALL LAYERS USE 1 OZ COPPER." at 2340,2340 h50
  text "4) SILKSCREEN:  TOP SIDE, COLOR: WHITE" at 2190,2190 h50
  text "5) SEE DRILL CHART FOR FINISHED HOLE SIZES." at 2190,2040 h50
  text "6) HOLE TOLERANCE IS +/- 3 MILS UNLESS OTHERWISE SPECIFIED." at 2190,1890 h50
  text "7) THIS IS A 4 LAYER BOARD." at 2190,1740 h50
  text "8) TRACE WIDTHS IN ARTWORK ARE FINISHED SIZES.  DO NOT DEVIATE" at 2190,1590 h50
  text "WITHOUT PRIOR AUTHORIZATION FROM SCINTERA." at 2340,1440 h50
  text "9) BOW AND TWIST: .75% MAX ALLOWABLE." at 2190,1290 h50
  text "1700mil" at 3.41,1152.5 h50
  text "10) FABRICATE PER IPC-6012 CLASS 2 ( LATEST REVISION ) UNLESS OTHERWISE SPECIFIED." at 2190,1140 h50
  text "11) REMOVE ALL BURRS AND SHARP EDGES." at 2190,990 h50
  text "12) VENDOR SHALL PERFORM FULL NETS LIST TEST - EXTRACT NETS LIST FROM GERBER." at 2190,840 h50
  text "13) FINISHED BOARD SHALL BE RoHS COMPLIANT." at 2190,690 h50
  text "14) COPPER TO THE EDGE BY DESIGN. NO RELIEF." at 2190,540 h50
  text "1000mil" at 1093.41,462.5 h50
  text "15) REMOVE UNUSED PADS." at 2190,390 h50
  text "16) TENT ALL 10 MIL VIAS USING SOLDERMASK ON THE LAYER4." at 2190,240 h50
  text "LAYER STACK UP" at 3190,-210 h65
  text "LAYER1 TOP" at 4840,-410 h50
  text "FR406 14MIL +/- 1MIL" at 3240,-560 h50
  text "LAYER2 GND" at 4840,-710 h50
  text "DRILL DWG" at 1234.25,-756.5 h50
  text "RF4 PRE-PREG" at 3390,-860 h50
  text "SCINTERA" at 59.84,-957.48 h50
  text "LAYER3 PWR/SIG" at 4840,-1010 h50
  text "SC1894-DB3400A  FAB DRILL DRAWING" at 59.84,-1107.48 h50
  text "42 +/- 4MIL" at 2340,-1110 h50 r90
  text "FR406 14MIL +/- 1MIL" at 3240,-1160 h50
  text "(RDB3.4 REV3)" at 59.84,-1248.23 h50
  text "LAYER4 BOTTOM" at 4840,-1310 h50
MECH:
  the board outline again, w2
  text "41" at 75,1050 h35
  text "29" at 795,1050 h35
  text "42" at -910,920 h35
  text "28" at 1050,915 h35
  text "47" at -910,80 h35
  text "14" at 1065,75 h35
  text "1" at 90,-90 h35
  text "13" at 810,-90 h35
